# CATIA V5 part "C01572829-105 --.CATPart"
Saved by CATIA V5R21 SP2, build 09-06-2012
Part number: C01572829-105
Revision: ---
Description: PROPRIETARY NOTICE (do not delete / modify)  ***************************************************************************************************  BOMBARDIER INC.,  PAR L'INTERMEDIAIRE DE SES GROUPES, DIVISIONS ET/OU FILIALES  CORPORATIVES, FOURNIT LES  PRESENTS  RENSEIGNEMENTS AU GOUVERNEMENT  A TITRE CONFIDENTIEL. CES RENSEIGNEMENTS  ONT UNE TENEUR CONFI-  DENTIELLE,  AVEC  DROITS DE  PROPRIETE, ET NOUS  LES CONSIDERONS  EXCLUS DE L'APPLICATION  DE LA  LOI SUR  L 'ACCES A L'INFORMATION. ILS PEUVENT AUSSI CONSTITUER UN SECRET INDUSTRIEL DE NOTRE SOCIETE OU DE TIERCES  PARTIES. LA DIVULGATION  PUBLIQUE DE  CES RENSEIGNEMENTS NUIRAIT A BOMBARDIER INC. OU  A DES TIERCES PAR-  TIES. TOUTE INTENTION  DE LES DIFFUSER EN TOUT OU EN PARTIE  DEVRA ETRE SIGNIFIEE A L'AVANCE ET PAR ECRIT  AU VICE-PRESIDENT SERVICES JURIDIQUES, BOMBARDIER AERONAUTIQUE.    BOMBARDIER INC., BY ITS GROUPS, DIVISIONS AND/OR CORPORATE SUBSIDIARIES, PROVIDES THIS INFORMATION TO THE  GOVERNMENT IN  CONFIDENCE. THIS  IS PROPRIETARY CONFIDENTIAL INFORMATION  WHICH WE CONSIDER EXCLUDED FROM  THE APPLICATION  OF THE ACCESS TO INFORMATION ACT AND MAY ALSO BE A TRADE  SECRET OF OUR COMPANY OR THIRD  PARTIES.  PUBLIC RELEASE  OF THIS INFORMATION WOULD BE  HARMFUL TO BOMBARDIER INC.  OR THIRD PARTIES. ANY  INTENTION TO  DISCLOSE SUCH INFORMATION, OR PART THEREOF, MUST BE INDICATED  IN ADVANCE AND IN WRITING TO  THE VICE-PRESIDENT LEGAL SERVICES, BOMBARDIER AEROSPACE.        LES RENSEIGNEMENTS,  LES DONNEES ET DESSINS TECHNIQUES DIVULGUES DANS LES PRESENTES SONT LA PROPRIETE EX-  CLUSIVE DE BOMBARDIER INC. OU COMPORTENT DES DROITS DE PROPRIETE  APPARTENANT A AUTRUI ET NE PEUVENT ETRE  DIVULGUES  A QUICONQUE NI UTILISES PAR QUI QUE CE SOIT SANS  LE CONSENTEMENT ECRIT DE BOMBARDIER INC.  LE  DETENTEUR  DES PRESENTES S'ENGAGE, DANS TOUTES  CIRCONSTANCES, A GARDER CONFIDENTIELS LES DONNEES ET DES-  SINS TECHNIQUES QU'ELLES CONTIENNENT.  CE QUI PRECEDE NE  S'APPLIQUE PAS AUX PERSONNES QUI ONT DES DROITS  DE PROPRIETE SUR CES RENSEIGNEMENTS, DONNEES TECHNIQUES ET DESSINS DANS LA MESURE OU CES DROITS EXISTENT.    THE INFORMATION,TECHNICAL DATA AND DESIGNS DISCLOSED HEREIN ARE THE EXCLUSIVE PROPERTY OF BOMBARDIER INC.  OR CONTAIN PROPRIETARY RIGHTS OF OTHERS AND ARE NOT TO BE USED OR DISCLOSED TO OTHERS WITHOUT THE WRITTEN  CONSENT OF BOMBARDIER INC.THE RECIPIENT OF THIS DOCUMENT, BY ITS RETENTION AND USE AGREES TO HOLD IN CON-  FIDENCE THE TECHNICAL DATA AND DESIGNS CONTAINED HEREIN. THE FOREGOING SHALL  NOT APPLY TO PERSONS HAVING  PROPRIETARY RIGHTS TO SUCH INFORMATION, TECHNICAL DATA OR DESIGNS TO THE EXTENT THAT SUCH RIGHTS EXIST.    Copyright 2005 Bombardier inc.  ***********************************
Property "Title": "ROD END, SLIDE DISARMING, OWE"
Property "Dataset Type": "DETAIL"
Property "Supplier Name And CAGE Code": "AIRBUS CANADA LIMITED PARTNERSHIP L0J48"
Property "Major Supplier Code": "LP"
Property "3D Only": "N/A"
Property "Material Form": "BAR - ROUND"
Property "Finish Code": "S010"
Property "PCCN": "2"
Property "Organization": "DESIGN"
Property "Design Authority Program": "BD-500"
Property "Color Coded": "N/A"
Property "Thickness": 0
Property "Inside Diameter": 0
Property "Outside Diameter": 1.25
Property "Length": 0
Property "Width": 0
Property "Wall": 0
Property "Wire Gauge": "-"
Property "Alloy": "15-5PH"
Property "Final Condition": "H1025"
Property "Density": "N/A"
Property "Form": "N/A"
Property "Grade/Composition": "N/A"
Property "Material Class": "N/A"
Property "Mesh Cell Size": "N/A"
Property "Standard Spec Die": "N/A"
Property "Type": "N/A"
Property "Style": "N/A"
Property "MFG Process": "MACHINED"
Property "Material Specification Production": "AMS5659"
Property "Material Description Production": "CRES"
Property "Dimensions": "DIMENSIONS ARE IN INCHES"
Property "Roughness": "ALL MACHINED SURFACES 125 Ra MAX"
Property "Eng. Tolerances": "LINEAR .XX= +/-.03; .XXX= +/-.010; ANGULAR= +/-0.5 DEG"
Property "Tool Design Tolerances": "LINEAR .X= +/-.06; .XX= +/-.015; .XXX= +/-.005; .XXXX= +/-.001; ANGULAR= +/-0.5 DEG"
Property "Project": "BA"
Publications: "PartBody"
Material "CRES-PH-15-5-BAR": density 7833.41 kg/m3
Bounding box of the stored display mesh (mm): x -4.19 to 4.19, y -11.421 to 11.421, z -11.43 to 114.3
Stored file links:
  C:\Users\CQQZ006\Desktop\A220钢钛件\舱门\C01572829-105\C01572829-105 --.CATPart
  I:\Standard\Materials\Textures\steel100.jpeg

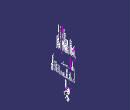
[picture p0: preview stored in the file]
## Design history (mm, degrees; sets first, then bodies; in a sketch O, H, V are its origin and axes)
Part_3D_Annotations1 "CATTPSSet"
AxisSystem1 "Absolute Axis System": origin (0, 0, 0), X (1, 0, 0), Y (0, 1, 0), Z (0, 0, 1)
Point1 "Point.2-UPR POINT": (0, 0, 114.3), in AxisSystem1
Point2 "Point.1-LWR POINT": (0, 0, 0), in AxisSystem1
Line1: type PtPt, FirstPoint Point2, SecondPoint Point1
Point3 "Point.5-CABLE END UPR EXTR.": type OnCurve, Support Line1, RefPoint Point1, Length 15.24
Sketch1 on yz-plane, origin (0, 0, 0), H (0, 1, 0), V (0, 0, 1)
  circle A1 centre (0, 0) radius 8.3337
  radius A1 = 8.3337
Pocket1: profile Sketch1, direction (-1, 0, 0), length 25.4, mirrored extent
Sketch2 on zx-plane, origin (0, 0, 0), H (-1, 0, 0), V (0, 0, 1)
  line L1 (-25.4, 22.86) -> (-14.605, 22.86)
  line L2 (-3.175, 11.43) -> (-3.175, -25.4)
  line L3 (-3.175, -25.4) -> (-25.4, -25.4)
  line L4 (-25.4, -25.4) -> (-25.4, 22.86)
  arc A1 centre (-14.605, 11.43) radius 11.43 from (-3.175, 11.43) to (-14.605, 22.86) ccw
  point P6 (-14.605, 11.43)
  line L5 (3.175, -25.4) -> (25.4, -25.4)
  line L6 (3.175, 11.43) -> (3.175, -25.4)
  line L7 (25.4, -25.4) -> (25.4, 22.86)
  line L8 (25.4, 22.86) -> (14.605, 22.86)
  arc A2 centre (14.605, 11.43) radius 11.43 from (3.175, 11.43) to (14.605, 22.86) cw
  distance V L2 = 3.175
  radius A1 = 11.43
  distance P6 H = 11.43
  distance L3 H = 25.4
  distance L4 V = 25.4
  horizontal: L1 H, L3 H
  vertical: L2 V, L4 V
  tangency: A1 L2, A1 L1
  symmetry: L3 L5 V, L2 L6 V, L4 L7 V, L1 L8 V, A1 A2 V
Pocket2: profile Sketch2, direction (0, -1, 0), length 25.4, mirrored extent
Set2 "Geometrical Set for 3D Annotations"
  Set3 "No Show Geometry"
    Extract1: ExtractElem face of Pocket3 from Sketch4.L2
  Set4 "Surfaces for 3D Annotations"
    Set5 "GS_CHANGE 4"
      Offset1: Offset Extract1, Length 0.0025
Body1 "PartBody" (main body)
  Sketch3 on yz-plane, origin (0, 0, 0), H (0, 1, 0), V (0, 0, 1)
    axis line L1 (0, 114.3) -> (0, -23.7737)
    point P1 (0, 114.3)
    line L2 (0, 114.3) -> (3.1725, 114.3)
    line L3 (3.1725, 114.3) -> (3.1725, 85.09)
    line L4 (3.1725, 85.09) -> (3.175, 85.09)
    line L5 (3.175, 85.09) -> (3.175, 34.3119)
    arc A1 centre (0, 0) radius 11.43 from (0, -11.43) to (11.43, 0) ccw
    line L6 (4.191, 15.5496) -> (4.191, 21.59)
    point P5 (4.191, 21.59)
    arc A2 centre (8.001, 15.5496) radius 3.81 from (5.5483, 12.634) to (4.191, 15.5496) cw
    point P7 (0, -11.43)
    line L7 (4.191, 21.59) -> (3.2717, 32.0982)
    arc A3 centre (-5.08, 0) radius 16.51 from (11.43, 0) to (5.5483, 12.634) ccw
    point P10 (-5.08, 0)
    arc A4 centre (28.575, 34.3119) radius 25.4 from (3.175, 34.3119) to (3.2717, 32.0982) ccw
    distance H L2 = 114.3
    distance L5 L1 = 3.175
    distance L3 L1 = 3.1725
    distance L2 L4 = 29.21
    distance L6 L1 = 4.191
    radius A1 = 11.43
    radius A2 = 3.81
    angle L7 L6 = 5
    distance P5 H = 21.59
    radius A3 = 16.51
    radius A4 = 25.4
    vertical: L1 V, L3 V, L5 V, L6 V
    coincidence: P1 L1, P7 L1, O L1, P10 H
    horizontal: L2 H, L4 H
    tangency: A2 L6, A3 A1, A2 A3, A4 L5, A4 L7
  Shaft1: profile Sketch3, axis Sketch3.L1, angle 360
  Body2
    Sketch4 on yz-plane, origin (0, 0, 0), H (0, 1, 0), V (0, 0, 1)
      line L1 (9.4894, 121.92) -> (1.8694, 121.92)
      line L2 (1.8694, 121.92) -> (1.8694, 83.82)
      arc A1 centre (9.4894, 83.82) radius 7.62 from (1.8694, 83.82) to (9.4894, 76.2) ccw
      point P4 (9.4894, 83.82)
      line L3 (9.4894, 76.2) -> (9.4894, 121.92)
      construction line L4 (20.4576, 83.82) -> (-14.9249, 83.82)
      reference projected line E1 (0, 114.3) -> (3.1496, 114.3) from Sketch3.L2
      reference projected line E2 (3.1725, 114.3) -> (3.1725, 85.09) from Sketch3.L3
      point P8 (3.1725, 114.3)
      point P9 (3.1725, 85.09)
      point P10 (-3.1725, 85.09)
      point P11 (-3.1725, 114.3)
      construction line L5 (-3.1725, 114.3) -> (-3.1725, 85.09)
      radius A1 = 7.62
      distance L1 L4 = 38.1
      distance L4 E1 = 30.48
      distance V L2 = 1.8694
      horizontal: L1 H, L4 H
      vertical: L2 V, L3 V
      tangency: A1 L2
      coincidence: P4 L3, P4 L4
      symmetry: P9 P10 V, P8 P11 V, E2 L5 V
    Pocket3: profile Sketch4, direction (-1, 0, 0), length 0.7874, mirrored extent
    Fillet1: radius 0.254, on edge [start face of Pocket3 | face of Pocket3 from Sketch4.L2]; edge [face of Pocket3 from Sketch4.L2 | end face of Pocket3]
  Assemble1: tool Body2
  Body3
  Assemble2: tool Body3
  Body4
  Assemble3: tool Body4
  Chamfer1: length 0.762, second length 0.762, on edge [face of Shaft1 from Sketch3.L2 | face of Shaft1 from Sketch3.L3]
  Chamfer2: length 0.762, second length 0.762, on edge [face of Pocket1 from Sketch1.A1 | face of Pocket2 from Sketch2.L6]; edge [face of Pocket2 from Sketch2.L2 | face of Pocket1 from Sketch1.A1]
